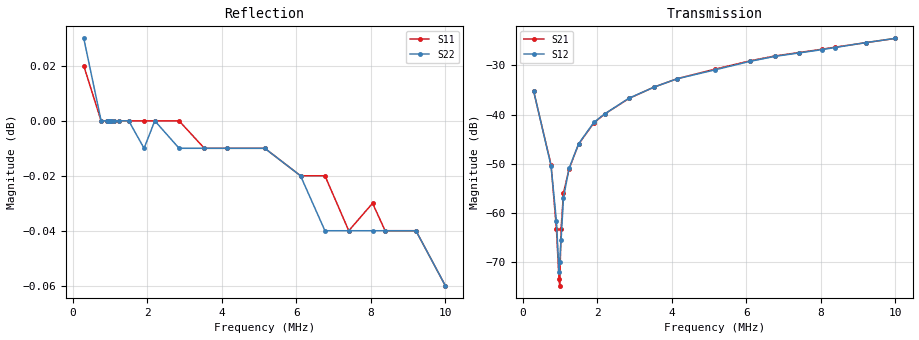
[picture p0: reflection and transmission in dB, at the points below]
!s-Parameter Generated by FASTRON Sdn. Bhd.
!FASTRON P/N : 1812AFTC-292X
!Keysight Technologies: E5071C_MY46733604_B.14.02
!Date: Wed Mar 18 14:00:49 2026
!Version  :Rev00  Wed Mar 18 14:00:49 2026
!Data & Calibration Information:
!Freq  S11:SOLT2(ON)  S21:SOLT2(ON)  S12:SOLT2(ON)  S22:SOLT2(ON)
!PortZ  Port1:50+j0  Port2:50+j0
!When reading reference impedance value at option line is always used.
! Remarks : This data is being provided solely for informational purposes.
# Hz S dB R 50
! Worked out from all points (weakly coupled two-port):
!   1601 points, 300 kHz to 10 MHz, reference 50 ohm
!   highest |S21| = -24.53 dB at 10 MHz (marker M1); lowest = -74.7 dB at 997.3 kHz (marker M2)
!   lowest |S11| = -0.1 dB at 10 MHz (marker M3), VSWR 308.72, Z = 2.79 - j201 ohm
!   |S11| at or under -10 dB: nowhere
!   |S22| runs from -0.1 to 0.0 dB; largest |S21 - S12| = 0.00077
!   S11 on the Smith chart (normalised r, x): 300 kHz: -0, +11; 2.206 MHz: -0.00, +1.34; 4.154 MHz: 0.00, +0.38; 6.115 MHz: 0.00, -0.20; 8.047 MHz: 0.00, -0.96; 10 MHz: 0.06, -4.03
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300000  0.02 10.7  -35.29 -87.1  -35.24 -87.3  0.03 -10.4
765375  0.00 25.7  -50.19 -86.3  -50.39 -89.1  0.00 -28.1
910654  0.00 30.5  -63.21 -91.6  -61.67 -88.5  -0.00 -33.5
979144  0.00 32.7  -73.45 -47.8  -72.00 -25.4  0.00 -36.0
997274  0.00 33.3  -74.75 61.9  -69.88 18.9  0.00 -36.7
1035548  0.00 34.6  -63.22 61.9  -65.38 84.8  -0.00 -38.1
1099099  -0.00 36.7  -55.93 64.2  -56.88 72.1  -0.00 -40.5
1248741  0.00 41.6  -51.07 81.4  -50.92 84.6  -0.00 -46.0
1505896  0.00 50.2  -45.99 82.2  -45.93 82.2  -0.00 -55.6
1917564  -0.00 63.8  -41.65 83.7  -41.56 83.9  -0.01 -70.8
2205594  0.00 73.4  -39.89 83.4  -39.86 83.7  -0.00 -81.5
2856713  -0.00 95.0  -36.72 82.2  -36.67 83.2  -0.01 -105.6
3534704  -0.01 117.5  -34.40 80.9  -34.40 80.9  -0.01 -130.8
4153644  -0.01 138.0  -32.70 80.3  -32.72 80.1  -0.01 -153.7
5155786  -0.01 171.3  -30.79 77.5  -30.93 77.8  -0.01 169.3
6115250  -0.02 -156.8  -29.07 75.1  -29.17 75.4  -0.02 133.7
6770355  -0.02 -135.1  -28.09 73.7  -28.18 73.5  -0.04 109.5
7409041  -0.04 -113.8  -27.41 71.7  -27.49 71.7  -0.04 85.9
8047393  -0.03 -92.6  -26.71 70.9  -26.79 71.1  -0.04 62.2
8385344  -0.04 -81.4  -26.31 70.4  -26.38 70.4  -0.04 49.7
9211447  -0.04 -54.0  -25.39 68.7  -25.38 68.7  -0.04 19.1
1e7  -0.06 -27.9  -24.53 66.4  -24.52 66.4  -0.06 -10.2
